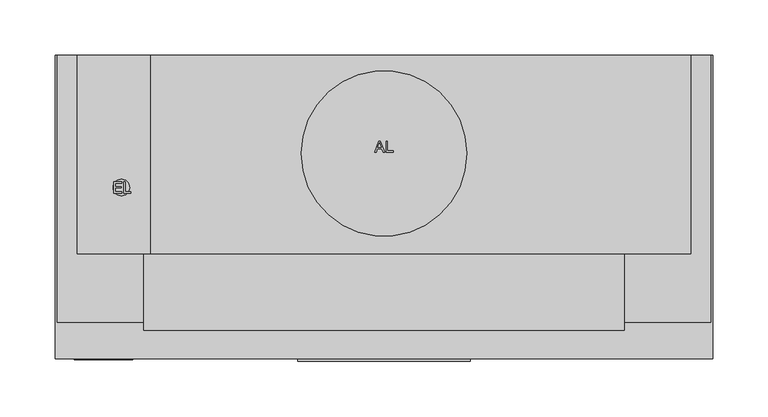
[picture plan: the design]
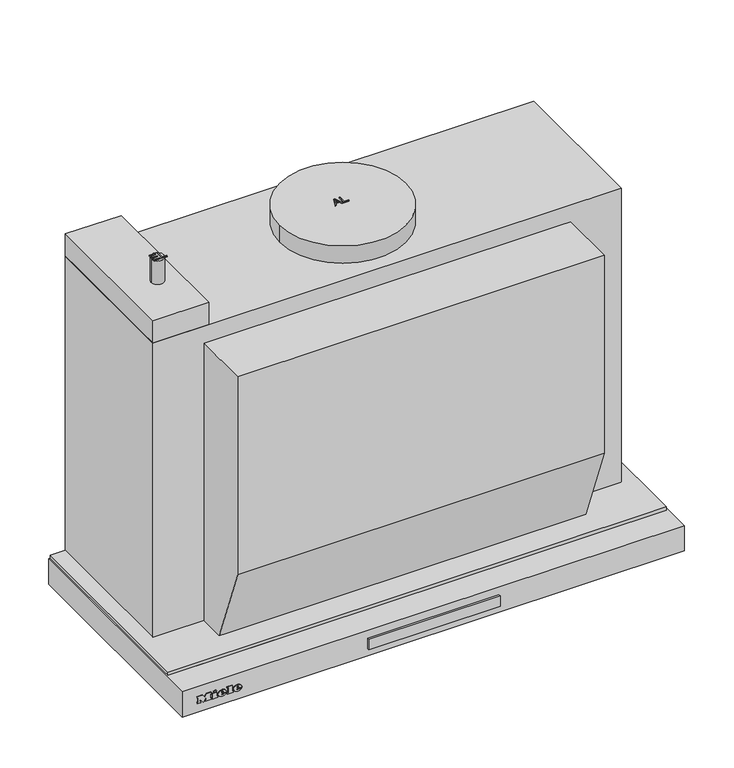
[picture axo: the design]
"""IFC4 building model written with IfcOpenShell, lengths in millimetres: proxy geometry."""

from ifc_helpers import new_model, si_unit, point, frame, frame_2d, origin, origin_with_axes, place, context, project, spatial, polyline, circle_curve, ellipse_curve, trimmed, segment, composite_curve, outline, extrude, faceted_brep, source, transform, mapped, element, save
from ifc_brep_helpers import plane_surface, cylinder_surface, revolved_surface, extruded_surface, advanced_brep


def specialty_equipment_e3befa43(model_context):
    return source(origin(), model_context, "Body", "SolidModel", [
        extrude(outline(polyline([(78.0, -275.0), (78.0, -277.3978707), (-78.0, -277.3978707), (-78.0, -275.0), (78.0, -275.0)])), frame((0.0, 0.0, -23.0389651), z_axis=(0.0, 0.0, 1.0), x_axis=(1.0, 0.0, 0.0)), (0.0, 0.0, 1.0), 13.3389155),
        advanced_brep(
        [(-233.4590019, -276.0, -18.7681017), (-233.4590019, -276.0, -17.8894017), (-227.6387019, -276.0, -17.8894017), (-237.7655019, -276.0, -17.8894017), (-235.3730019, -276.0, -20.8300017), (-227.7866019, -276.0, -18.7681017), (-230.4140019, -276.0, -18.7681017), (-232.4846019, -276.0, -19.7425017), (-233.4590019, -276.0, -16.7758017), (-233.4590019, -276.0, -15.8275017), (-231.9713019, -276.0, -15.8275017), (-231.9713019, -276.0, -16.7758017), (-233.4590019, -275.0, -18.7681017), (-232.4846019, -275.0, -19.7425017), (-230.4140019, -275.0, -18.7681017), (-227.7866019, -275.0, -18.7681017), (-235.3730019, -275.0, -20.8300017), (-237.7655019, -275.0, -17.8894017), (-227.6387019, -275.0, -17.8894017), (-233.4590019, -275.0, -17.8894017), (-233.4590019, -275.0, -16.7758017), (-231.9713019, -275.0, -16.7758017), (-231.9713019, -275.0, -15.8275017), (-233.4590019, -275.0, -15.8275017)],
        [
            (0, 1),
            (1, 2),
            (2, 3, ellipse_curve(frame((-232.7021019, -276.0, -17.8894017), z_axis=(0.0, -1.0, 0.0), x_axis=(-1.0, 0.0, 0.0)), 5.0634, 4.1847)),
            (3, 4, circle_curve(frame((-234.3985544, -276.0, -17.5936017), z_axis=(0.0, -1.0, 0.0), x_axis=(0.0, 0.0, -1.0)), 3.3799161)),
            (4, 5, circle_curve(frame((-232.8034638, -276.0, -15.2968017), z_axis=(0.0, -1.0, 0.0), x_axis=(0.0, 0.0, -1.0)), 6.1007236)),
            (5, 6),
            (6, 7, circle_curve(frame((-232.0593254, -276.0, -17.9590017), z_axis=(0.0, 1.0, 0.0), x_axis=(0.0, 0.0, -1.0)), 1.8335027)),
            (7, 0, circle_curve(frame((-232.4846019, -276.0, -18.7681017), z_axis=(0.0, 1.0, 0.0), x_axis=(0.0, 0.0, -1.0)), 0.9744)),
            (8, 9),
            (9, 10, circle_curve(frame((-232.7151519, -276.0, -15.8275017), z_axis=(0.0, 1.0, 0.0), x_axis=(0.0, 0.0, -1.0)), 0.74385)),
            (10, 11),
            (11, 8),
            (12, 13, circle_curve(frame((-232.4846019, -275.0, -18.7681017), z_axis=(0.0, -1.0, 0.0), x_axis=(0.0, 0.0, -1.0)), 0.9744)),
            (13, 14, circle_curve(frame((-232.0593254, -275.0, -17.9590017), z_axis=(0.0, -1.0, 0.0), x_axis=(0.0, 0.0, -1.0)), 1.8335027)),
            (14, 15),
            (15, 16, circle_curve(frame((-232.8034638, -275.0, -15.2968017), z_axis=(0.0, 1.0, 0.0), x_axis=(0.0, 0.0, -1.0)), 6.1007236)),
            (16, 17, circle_curve(frame((-234.3985544, -275.0, -17.5936017), z_axis=(0.0, 1.0, 0.0), x_axis=(0.0, 0.0, -1.0)), 3.3799161)),
            (17, 18, ellipse_curve(frame((-232.7021019, -275.0, -17.8894017), z_axis=(0.0, 1.0, 0.0), x_axis=(-1.0, 0.0, 0.0)), 5.0634, 4.1847)),
            (18, 19),
            (19, 12),
            (20, 21),
            (21, 22),
            (22, 23, circle_curve(frame((-232.7151519, -275.0, -15.8275017), z_axis=(0.0, -1.0, 0.0), x_axis=(0.0, 0.0, -1.0)), 0.74385)),
            (23, 20),
            (0, 12),
            (19, 1),
            (18, 2),
            (5, 15),
            (14, 6),
            (17, 3),
            (13, 7),
            (16, 4),
            (8, 20),
            (23, 9),
            (22, 10),
            (21, 11),
        ],
        [
            plane_surface(frame((-233.4590019, -276.0, -17.8894017), z_axis=(0.0, -1.0, 0.0), x_axis=(0.0, 0.0, 1.0))),
            plane_surface(frame((-233.4590019, -275.0, -17.8894017), z_axis=(0.0, 1.0, 0.0), x_axis=(0.0, 0.0, -1.0))),
            plane_surface(frame((-233.4590019, -276.0, -18.7681017), z_axis=(1.0, 0.0, 0.0), x_axis=(0.0, 1.0, 0.0))),
            plane_surface(frame((-233.4590019, -276.0, -17.8894017), z_axis=(0.0, 0.0, -1.0), x_axis=(0.0, 1.0, 0.0))),
            plane_surface(frame((-227.7866019, -276.0, -18.7681017), z_axis=(0.0, 0.0, 1.0), x_axis=(0.0, 1.0, 0.0))),
            extruded_surface(trimmed(ellipse_curve(frame((-232.7021019, -274.0, -17.8894017), z_axis=(0.0, -1.0, 0.0), x_axis=(-1.0, 0.0, 0.0)), 5.0634, 4.1847), [point((-227.6387019, -274.0, -17.8894017))], [point((-237.7655019, -274.0, -17.8894017))], True, "CARTESIAN"), (0.0, -1.0, 0.0), 1.0),
            revolved_surface(polyline([(-232.0593254, -275.0, -19.792504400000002), (-232.0593254, -276.0, -19.792504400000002)]), (-232.0593254, -275.0, -17.9590017), (0.0, 1.0, 0.0)),
            revolved_surface(polyline([(-232.4846019, -275.0, -19.7425017), (-232.4846019, -276.0, -19.7425017)]), (-232.4846019, -275.0, -18.7681017), (0.0, 1.0, 0.0)),
            cylinder_surface(frame((-234.3985544, -275.0, -17.5936017), z_axis=(0.0, -1.0, 0.0), x_axis=(0.0, 0.0, -1.0)), 3.3799161),
            cylinder_surface(frame((-232.8034638, -275.0, -15.2968017), z_axis=(0.0, -1.0, 0.0), x_axis=(0.0, 0.0, -1.0)), 6.1007236),
            plane_surface(frame((-233.4590019, -276.0, -16.7758017), z_axis=(1.0, 0.0, 0.0), x_axis=(0.0, 1.0, 0.0))),
            revolved_surface(polyline([(-232.7151519, -275.0, -16.571351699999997), (-232.7151519, -276.0, -16.571351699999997)]), (-232.7151519, -275.0, -15.8275017), (0.0, 1.0, 0.0)),
            plane_surface(frame((-231.9713019, -276.0, -15.8275017), z_axis=(-1.0, 0.0, 0.0), x_axis=(0.0, 1.0, 0.0))),
            plane_surface(frame((-231.9713019, -276.0, -16.7758017), z_axis=(0.0, 0.0, 1.0), x_axis=(0.0, 1.0, 0.0))),
        ],
        [
            (0, [[1, 2, 3, 4, 5, 6, 7, 8], [9, 10, 11, 12]]),
            (1, [[13, 14, 15, 16, 17, 18, 19, 20], [21, 22, 23, 24]]),
            (2, [[-1, 25, -20, 26]]),
            (3, [[-2, -26, -19, 27]]),
            (4, [[-6, 28, -15, 29]]),
            (5, [[-3, -27, -18, 30]]),
            (6, [[-7, -29, -14, 31]]),
            (7, [[-8, -31, -13, -25]]),
            (8, [[-4, -30, -17, 32]]),
            (9, [[-5, -32, -16, -28]]),
            (10, [[-9, 33, -24, 34]]),
            (11, [[-10, -34, -23, 35]]),
            (12, [[-11, -35, -22, 36]]),
            (13, [[-12, -36, -21, -33]]),
        ],
    ),
        advanced_brep(
        [(-251.6159019, -276.0, -18.7681017), (-251.6159019, -276.0, -17.8894017), (-245.7956019, -276.0, -17.8894017), (-255.9224019, -276.0, -17.8894017), (-253.5299019, -276.0, -20.8300017), (-245.9435019, -276.0, -18.7681017), (-248.5709019, -276.0, -18.7681017), (-250.6415019, -276.0, -19.7425017), (-251.6159019, -276.0, -16.7758017), (-251.6159019, -276.0, -15.8275017), (-250.1282019, -276.0, -15.8275017), (-250.1282019, -276.0, -16.7758017), (-251.6159019, -275.0, -18.7681017), (-250.6415019, -275.0, -19.7425017), (-248.5709019, -275.0, -18.7681017), (-245.9435019, -275.0, -18.7681017), (-253.5299019, -275.0, -20.8300017), (-255.9224019, -275.0, -17.8894017), (-245.7956019, -275.0, -17.8894017), (-251.6159019, -275.0, -17.8894017), (-251.6159019, -275.0, -16.7758017), (-250.1282019, -275.0, -16.7758017), (-250.1282019, -275.0, -15.8275017), (-251.6159019, -275.0, -15.8275017)],
        [
            (0, 1),
            (1, 2),
            (2, 3, ellipse_curve(frame((-250.8590019, -276.0, -17.8894017), z_axis=(0.0, -1.0, 0.0), x_axis=(-1.0, 0.0, 0.0)), 5.0634, 4.1847)),
            (3, 4, circle_curve(frame((-252.5554544, -276.0, -17.5936017), z_axis=(0.0, -1.0, 0.0), x_axis=(0.0, 0.0, -1.0)), 3.3799161)),
            (4, 5, circle_curve(frame((-250.9603638, -276.0, -15.2968017), z_axis=(0.0, -1.0, 0.0), x_axis=(0.0, 0.0, -1.0)), 6.1007236)),
            (5, 6),
            (6, 7, circle_curve(frame((-250.2162254, -276.0, -17.9590017), z_axis=(0.0, 1.0, 0.0), x_axis=(0.0, 0.0, -1.0)), 1.8335027)),
            (7, 0, circle_curve(frame((-250.6415019, -276.0, -18.7681017), z_axis=(0.0, 1.0, 0.0), x_axis=(0.0, 0.0, -1.0)), 0.9744)),
            (8, 9),
            (9, 10, circle_curve(frame((-250.8720519, -276.0, -15.8275017), z_axis=(0.0, 1.0, 0.0), x_axis=(0.0, 0.0, -1.0)), 0.74385)),
            (10, 11),
            (11, 8),
            (12, 13, circle_curve(frame((-250.6415019, -275.0, -18.7681017), z_axis=(0.0, -1.0, 0.0), x_axis=(0.0, 0.0, -1.0)), 0.9744)),
            (13, 14, circle_curve(frame((-250.2162254, -275.0, -17.9590017), z_axis=(0.0, -1.0, 0.0), x_axis=(0.0, 0.0, -1.0)), 1.8335027)),
            (14, 15),
            (15, 16, circle_curve(frame((-250.9603638, -275.0, -15.2968017), z_axis=(0.0, 1.0, 0.0), x_axis=(0.0, 0.0, -1.0)), 6.1007236)),
            (16, 17, circle_curve(frame((-252.5554544, -275.0, -17.5936017), z_axis=(0.0, 1.0, 0.0), x_axis=(0.0, 0.0, -1.0)), 3.3799161)),
            (17, 18, ellipse_curve(frame((-250.8590019, -275.0, -17.8894017), z_axis=(0.0, 1.0, 0.0), x_axis=(-1.0, 0.0, 0.0)), 5.0634, 4.1847)),
            (18, 19),
            (19, 12),
            (20, 21),
            (21, 22),
            (22, 23, circle_curve(frame((-250.8720519, -275.0, -15.8275017), z_axis=(0.0, -1.0, 0.0), x_axis=(0.0, 0.0, -1.0)), 0.74385)),
            (23, 20),
            (0, 12),
            (19, 1),
            (18, 2),
            (5, 15),
            (14, 6),
            (17, 3),
            (13, 7),
            (16, 4),
            (8, 20),
            (23, 9),
            (22, 10),
            (21, 11),
        ],
        [
            plane_surface(frame((-251.6159019, -276.0, -17.8894017), z_axis=(0.0, -1.0, 0.0), x_axis=(0.0, 0.0, 1.0))),
            plane_surface(frame((-251.6159019, -275.0, -17.8894017), z_axis=(0.0, 1.0, 0.0), x_axis=(0.0, 0.0, -1.0))),
            plane_surface(frame((-251.6159019, -276.0, -18.7681017), z_axis=(1.0, 0.0, 0.0), x_axis=(0.0, 1.0, 0.0))),
            plane_surface(frame((-251.6159019, -276.0, -17.8894017), z_axis=(0.0, 0.0, -1.0), x_axis=(0.0, 1.0, 0.0))),
            plane_surface(frame((-245.9435019, -276.0, -18.7681017), z_axis=(0.0, 0.0, 1.0), x_axis=(0.0, 1.0, 0.0))),
            extruded_surface(trimmed(ellipse_curve(frame((-250.8590019, -274.0, -17.8894017), z_axis=(0.0, -1.0, 0.0), x_axis=(-1.0, 0.0, 0.0)), 5.0634, 4.1847), [point((-245.7956019, -274.0, -17.8894017))], [point((-255.9224019, -274.0, -17.8894017))], True, "CARTESIAN"), (0.0, -1.0, 0.0), 1.0),
            revolved_surface(polyline([(-250.2162254, -275.0, -19.792504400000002), (-250.2162254, -276.0, -19.792504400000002)]), (-250.2162254, -275.0, -17.9590017), (0.0, 1.0, 0.0)),
            revolved_surface(polyline([(-250.6415019, -275.0, -19.7425017), (-250.6415019, -276.0, -19.7425017)]), (-250.6415019, -275.0, -18.7681017), (0.0, 1.0, 0.0)),
            cylinder_surface(frame((-252.5554544, -275.0, -17.5936017), z_axis=(0.0, -1.0, 0.0), x_axis=(0.0, 0.0, -1.0)), 3.3799161),
            cylinder_surface(frame((-250.9603638, -275.0, -15.2968017), z_axis=(0.0, -1.0, 0.0), x_axis=(0.0, 0.0, -1.0)), 6.1007236),
            plane_surface(frame((-251.6159019, -276.0, -16.7758017), z_axis=(1.0, 0.0, 0.0), x_axis=(0.0, 1.0, 0.0))),
            revolved_surface(polyline([(-250.8720519, -275.0, -16.571351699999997), (-250.8720519, -276.0, -16.571351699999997)]), (-250.8720519, -275.0, -15.8275017), (0.0, 1.0, 0.0)),
            plane_surface(frame((-250.1282019, -276.0, -15.8275017), z_axis=(-1.0, 0.0, 0.0), x_axis=(0.0, 1.0, 0.0))),
            plane_surface(frame((-250.1282019, -276.0, -16.7758017), z_axis=(0.0, 0.0, 1.0), x_axis=(0.0, 1.0, 0.0))),
        ],
        [
            (0, [[1, 2, 3, 4, 5, 6, 7, 8], [9, 10, 11, 12]]),
            (1, [[13, 14, 15, 16, 17, 18, 19, 20], [21, 22, 23, 24]]),
            (2, [[-1, 25, -20, 26]]),
            (3, [[-2, -26, -19, 27]]),
            (4, [[-6, 28, -15, 29]]),
            (5, [[-3, -27, -18, 30]]),
            (6, [[-7, -29, -14, 31]]),
            (7, [[-8, -31, -13, -25]]),
            (8, [[-4, -30, -17, 32]]),
            (9, [[-5, -32, -16, -28]]),
            (10, [[-9, 33, -24, 34]]),
            (11, [[-10, -34, -23, 35]]),
            (12, [[-11, -35, -22, 36]]),
            (13, [[-12, -36, -21, -33]]),
        ],
    ),
        extrude(outline(polyline([(-12.6433017, -261.1250019), (-14.0527017, -260.4638019), (-12.6781017, -257.5145019), (-11.2687017, -258.1670019), (-12.6433017, -261.1250019)])), frame((0.0, -276.0, 0.0), z_axis=(0.0, 1.0, 0.0), x_axis=(0.0, 0.0, 1.0)), (0.0, 0.0, 1.0), 1.0),
        extrude(outline(polyline([(-14.2441017, -263.2739019), (-15.8014017, -263.2739019), (-15.8014017, -262.2386019), (-19.3684017, -262.2386019), (-19.3684017, -263.2739019), (-20.8300017, -263.2739019), (-20.8300017, -256.4096019), (-19.3684017, -256.4096019), (-19.3684017, -257.4188019), (-14.2441017, -257.4188019), (-14.2441017, -263.2739019)])), frame((0.0, -276.0, 0.0), z_axis=(0.0, 1.0, 0.0), x_axis=(0.0, 0.0, 1.0)), (0.0, 0.0, 1.0), 1.0),
        extrude(outline(polyline([(-13.5481017, -245.3084019), (-13.5481017, -244.2644019), (-19.3684017, -244.2644019), (-19.3684017, -245.3084019), (-20.8300017, -245.3084019), (-20.8300017, -238.2527019), (-19.3684017, -238.2527019), (-19.3684017, -239.3228019), (-12.1300017, -239.3228019), (-12.1300017, -245.3084019), (-13.5481017, -245.3084019)])), frame((0.0, -276.0, 0.0), z_axis=(0.0, 1.0, 0.0), x_axis=(0.0, 0.0, 1.0)), (0.0, 0.0, 1.0), 1.0),
        extrude(outline(polyline([(-13.5481017, -280.6130019), (-13.5481017, -279.5603019), (-19.3684017, -279.5603019), (-19.3684017, -280.6130019), (-20.8300017, -280.6130019), (-20.8300017, -276.7850019), (-19.3684017, -276.7850019), (-19.3684017, -277.8290019), (-15.6719769, -277.8290019), (-20.8300017, -273.9401019), (-15.5772794, -270.0338019), (-19.3684017, -270.0338019), (-19.3684017, -271.1039019), (-20.8300017, -271.1039019), (-20.8300017, -264.1613019), (-19.3684017, -264.1613019), (-19.3684017, -265.2662019), (-13.5481017, -265.2662019), (-13.5481017, -264.1613019), (-12.1300017, -264.1613019), (-12.1300017, -269.4596019), (-15.3925017, -272.0000019), (-12.1300017, -274.5491019), (-12.1300017, -280.6130019), (-13.5481017, -280.6130019)])), frame((0.0, -276.0, 0.0), z_axis=(0.0, 1.0, 0.0), x_axis=(0.0, 0.0, 1.0)), (0.0, 0.0, 1.0), 1.0),
        extrude(outline(polyline([(278.0, -180.0), (-278.0, -180.0), (-278.0, 0.0), (278.0, 0.0), (278.0, -180.0)])), frame((0.0, 0.0, 4.0), z_axis=(0.0, 0.0, 1.0), x_axis=(1.0, 0.0, 0.0)), (0.0, 0.0, 1.0), 369.0),
        extrude(outline(composite_curve([segment(trimmed(circle_curve(frame_2d((0.0, -89.0)), 75.0), [point((-75.0, -89.0))], [point((75.0, -89.0))], False, "CARTESIAN"), True, "CONTINUOUS"), segment(trimmed(circle_curve(frame_2d((0.0, -89.0)), 75.0), [point((75.0, -89.0))], [point((-75.0, -89.0))], False, "CARTESIAN"), True, "CONTINUOUS")], self_intersect=False)), frame((0.0, 0.0, 373.0), z_axis=(0.0, 0.0, 1.0), x_axis=(1.0, 0.0, 0.0)), (0.0, 0.0, 1.0), 22.0),
        extrude(outline(polyline([(-278.0, -180.0), (-278.0, 0.0), (-212.0, 0.0), (-212.0, -180.0), (-278.0, -180.0)])), frame((0.0, 0.0, 373.0), z_axis=(0.0, 0.0, 1.0), x_axis=(1.0, 0.0, 0.0)), (0.0, 0.0, 1.0), 28.0),
        extrude(outline(polyline([(-180.0, 352.0), (-180.0, 4.0), (-211.7966838, 4.0), (-249.5, 103.2192532), (-249.5, 352.0), (-180.0, 352.0)])), frame((-217.7156244, 0.0, 0.0), z_axis=(1.0, 0.0, 0.0), x_axis=(0.0, 1.0, 0.0)), (0.0, 0.0, 1.0), 435.4312488),
        extrude(outline(polyline([(-8.547125, -87.975609), (-4.5372113, -77.929978), (-3.4679009, -77.929978), (0.5420128, -87.975609), (-0.7848149, -87.975609), (-1.9350593, -84.8363493), (-6.0725055, -84.8363493), (-7.2202973, -87.975609), (-8.547125, -87.975609)]), holes=[polyline([(-5.6114267, -83.5806455), (-2.3936855, -83.5806455), (-3.2986752, -81.110931), (-4.0025561, -79.1856819), (-4.6279555, -80.8951069), (-5.6114267, -83.5806455)])]), frame((0.0, 0.0, 395.0), z_axis=(0.0, 0.0, 1.0), x_axis=(1.0, 0.0, 0.0)), (0.0, 0.0, 1.0), 1.0),
        extrude(outline(polyline([(1.8835558, -87.975609), (1.8835558, -77.929978), (3.1392597, -77.929978), (3.1392597, -86.7199052), (8.1620752, -86.7199052), (8.1620752, -87.975609), (1.8835558, -87.975609)])), frame((0.0, 0.0, 395.0), z_axis=(0.0, 0.0, 1.0), x_axis=(1.0, 0.0, 0.0)), (0.0, 0.0, 1.0), 1.0),
        extrude(outline(polyline([(296.0, 0.0), (296.0, -242.0), (-296.0, -242.0), (-296.0, 0.0), (296.0, 0.0)])), origin_with_axes(), (0.0, 0.0, 1.0), 4.0),
        extrude(outline(polyline([(120.0, -19.25), (120.0, -31.75), (-120.0, -31.75), (-120.0, -19.25), (120.0, -19.25)])), frame((0.0, 0.0, -23.0), z_axis=(0.0, 0.0, 1.0), x_axis=(1.0, 0.0, 0.0)), (0.0, 0.0, 1.0), 1.785426),
        extrude(outline(polyline([(181.0813184, -268.0), (181.0813184, -246.0), (249.0, -246.0), (249.0, -268.0), (181.0813184, -268.0)])), frame((0.0, 0.0, -33.3019181), z_axis=(0.0, 0.0, 1.0), x_axis=(1.0, 0.0, 0.0)), (0.0, 0.0, 1.0), 1.3019181),
        extrude(outline(polyline([(-249.0, -268.0), (-249.0, -246.0), (-181.0, -246.0), (-181.0, -268.0), (-249.0, -268.0)])), frame((0.0, 0.0, -33.3019181), z_axis=(0.0, 0.0, 1.0), x_axis=(1.0, 0.0, 0.0)), (0.0, 0.0, 1.0), 1.3019181),
        extrude(outline(composite_curve([segment(trimmed(circle_curve(frame_2d((-238.0, -120.0)), 7.5), [point((-230.5, -120.0))], [point((-245.5, -120.0))], False, "CARTESIAN"), True, "CONTINUOUS"), segment(trimmed(circle_curve(frame_2d((-238.0, -120.0)), 7.5), [point((-245.5, -120.0))], [point((-230.5, -120.0))], False, "CARTESIAN"), True, "CONTINUOUS")], self_intersect=False)), frame((0.0, 0.0, 401.0), z_axis=(0.0, 0.0, 1.0), x_axis=(1.0, 0.0, 0.0)), (0.0, 0.0, 1.0), 30.0),
        extrude(outline(polyline([(-235.640443, -124.9184735), (-235.640443, -114.8728425), (-234.3847391, -114.8728425), (-234.3847391, -123.6627696), (-229.3619236, -123.6627696), (-229.3619236, -124.9184735), (-235.640443, -124.9184735)])), frame((0.0, 0.0, 431.0), z_axis=(0.0, 0.0, 1.0), x_axis=(1.0, 0.0, 0.0)), (0.0, 0.0, 1.0), 1.0),
        extrude(outline(polyline([(-244.9012591, -124.9184735), (-244.9012591, -114.8728425), (-237.6809618, -114.8728425), (-237.6809618, -116.1285464), (-243.6455552, -116.1285464), (-243.6455552, -119.1108431), (-237.9948878, -119.1108431), (-237.9948878, -120.366547), (-243.6455552, -120.366547), (-243.6455552, -123.6627696), (-237.5239988, -123.6627696), (-237.5239988, -124.9184735), (-244.9012591, -124.9184735)])), frame((0.0, 0.0, 431.0), z_axis=(0.0, 0.0, 1.0), x_axis=(1.0, 0.0, 0.0)), (0.0, 0.0, 1.0), 1.0),
        extrude(outline(polyline([(-298.0, 0.0), (-263.0, 0.0), (-263.0, -242.0), (263.0, -242.0), (263.0, 0.0), (298.0, 0.0), (298.0, -275.0), (-298.0, -275.0), (-298.0, 0.0)])), frame((0.0, 0.0, -32.0), z_axis=(0.0, 0.0, 1.0), x_axis=(1.0, 0.0, 0.0)), (0.0, 0.0, 1.0), 32.0),
        faceted_brep([(-126.0, -39.0, -24.0), (-126.0, -39.0, 0.0), (126.0, -39.0, 0.0), (126.0, -39.0, -24.0), (-126.0, -12.0, -24.0), (-126.0, -12.0, 0.0), (126.0, -12.0, -24.0), (126.0, -12.0, 0.0), (-263.0, -242.0, 0.0), (-263.0, 0.0, 0.0), (-263.0, 0.0, -24.0), (-263.0, -52.0, -24.0), (-263.0, -52.0, -25.0), (-263.0, -242.0, -25.0), (263.0, -52.0, -25.0), (263.0, -242.0, -25.0), (263.0, -52.0, -24.0), (263.0, 0.0, -24.0), (263.0, 0.0, 0.0), (263.0, -242.0, 0.0)], [[[0, 1, 2, 3]], [[4, 5, 1, 0]], [[6, 7, 5, 4]], [[8, 9, 10, 11, 12, 13]], [[13, 12, 14, 15]], [[16, 11, 10, 17], [6, 4, 0, 3]], [[11, 16, 14, 12]], [[18, 9, 8, 19], [5, 7, 2, 1]], [[9, 18, 17, 10]], [[19, 8, 13, 15]], [[18, 19, 15, 14, 16, 17]], [[7, 6, 3, 2]]]),
        extrude(outline(polyline([(126.0, -12.0), (126.0, -39.0), (-126.0, -39.0), (-126.0, -12.0), (126.0, -12.0)]), holes=[polyline([(120.0, -19.25), (-120.0, -19.25), (-120.0, -31.75), (120.0, -31.75), (120.0, -19.25)])]), frame((0.0, 0.0, -21.214574), z_axis=(0.0, 0.0, 1.0), x_axis=(1.0, 0.0, 0.0)), (0.0, 0.0, 1.0), 21.214574),
    ])


if __name__ == "__main__":
    model = new_model("IFC4")
    model_context = context("Model", 3, world=origin())
    ifc_project = project(units=[si_unit("LENGTHUNIT", "METRE", prefix="MILLI")], contexts=[model_context])
    site = spatial("IfcSite", under=ifc_project)
    building = spatial("IfcBuilding", under=site)
    placement = place(None, origin())
    specialty_equipment_shape = specialty_equipment_e3befa43(model_context)
    element("IfcBuildingElementProxy", 1, Name="Specialty Equipment", at=placement, inside=building, context=model_context, shape_type="MappedRepresentation", body=[
        mapped(specialty_equipment_shape, transform((0.0, 0.0, 0.0), x_axis=(1.0, 0.0, 0.0), y_axis=(0.0, 1.0, 0.0), z_axis=(0.0, 0.0, 1.0))),
    ])
    save(model, "model.ifc")
